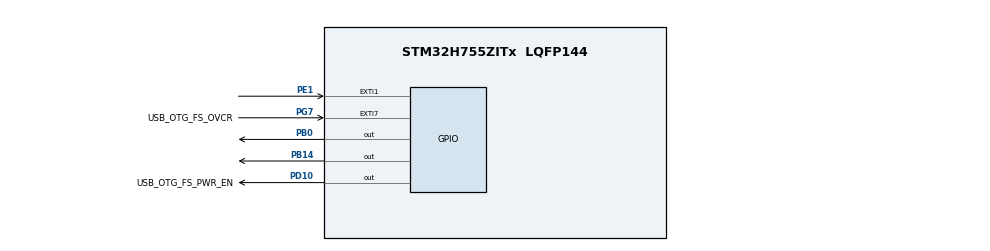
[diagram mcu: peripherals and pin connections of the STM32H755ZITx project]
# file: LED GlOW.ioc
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CortexM4.IPs=FATFS_M4\:I,FREERTOS_M4\:I,IWDG2\:I,RCC,WWDG2\:I,DMA,BDMA,MDMA,NVIC2\:I,ETH,USART3,DEBUG,PDM2PCM_M4\:I,PWR,RESMGR_UTILITY,SYS_M4\:I,USB_DEVICE_M4\:I,USB_HOST_M4\:I,CORTEX_M4\:I,GPIO,OPENAMP_M4\:I,VREFBUF,NUCLEO-H755ZI-Q
CortexM7.IPs=FATFS_M7\:I,FREERTOS_M7\:I,IWDG1\:I,RCC\:I,WWDG1\:I,DMA\:I,BDMA\:I,MDMA\:I,NVIC1\:I,ETH\:I,USART3\:I,USB_OTG_FS\:I,USB_OTG_FS1\:I,SYS\:I,CORTEX_M7\:I,DEBUG\:I,PDM2PCM_M7\:I,PWR\:I,RESMGR_UTILITY\:I,USB_DEVICE_M7\:I,USB_HOST_M7\:I,GPIO\:I,OPENAMP_M7\:I,VREFBUF\:I,NUCLEO-H755ZI-Q\:I
CortexM7.Pins=PB0,PB14,PE1
Mcu.Family=STM32H7
Mcu.Name=STM32H755ZITx
Mcu.Package=LQFP144
NUCLEO-H755ZI-Q.BUTTON=1
NUCLEO-H755ZI-Q.LD1=true
NUCLEO-H755ZI-Q.LD2=true
NUCLEO-H755ZI-Q.LD3=true
NUCLEO-H755ZI-Q.VCP=true
NVIC1.EXTI15_10_IRQn=true\:0\:0\:false\:false\:true\:false\:true\:true
NVIC1.PriorityGroup=NVIC_PRIORITYGROUP_4
NVIC2.PriorityGroup=NVIC_PRIORITYGROUP_4
PA1.PinAttribute=CortexM7
PA1.Signal=ETH_REF_CLK
PA11.PinAttribute=CortexM7
PA11.Signal=USB_OTG_FS_DM
PA12.PinAttribute=CortexM7
PA12.Signal=USB_OTG_FS_DP
PA2.PinAttribute=CortexM7
PA2.Signal=ETH_MDIO
PA7.PinAttribute=CortexM7
PA7.Signal=ETH_CRS_DV
PA8.PinAttribute=CortexM7
PA8.Signal=USB_OTG_FS_SOF
PA9.PinAttribute=CortexM7
PA9.Signal=USB_OTG_FS_VBUS
PB0.PinAttribute=CortexM7
PB0.Signal=GPIO_Output
PB13.PinAttribute=CortexM7
PB13.Signal=ETH_TXD1
PB14.PinAttribute=CortexM7
PB14.Signal=GPIO_Output
PC1.PinAttribute=CortexM7
PC1.Signal=ETH_MDC
PC14-OSC32_IN\ (OSC32_IN).PinAttribute=Free
PC14-OSC32_IN\ (OSC32_IN).Signal=RCC_OSC32_IN
PC15-OSC32_OUT\ (OSC32_OUT).PinAttribute=Free
PC15-OSC32_OUT\ (OSC32_OUT).Signal=RCC_OSC32_OUT
PC4.PinAttribute=CortexM7
PC4.Signal=ETH_RXD0
PC5.PinAttribute=CortexM7
PC5.Signal=ETH_RXD1
PD10.GPIO_Label=USB_OTG_FS_PWR_EN
PD10.PinAttribute=Free
PD10.Signal=GPIO_Output
PD8.Signal=USART3_TX
PD9.Signal=USART3_RX
PE1.PinAttribute=CortexM7
PE1.Signal=GPXTI1
PG11.PinAttribute=CortexM7
PG11.Signal=ETH_TX_EN
PG13.PinAttribute=CortexM7
PG13.Signal=ETH_TXD0
PG7.GPIO_Label=USB_OTG_FS_OVCR
PG7.PinAttribute=Free
PG7.Signal=GPXTI7
PH0-OSC_IN\ (PH0).PinAttribute=Free
PH0-OSC_IN\ (PH0).Signal=RCC_OSC_IN
PH1-OSC_OUT\ (PH1).PinAttribute=Free
PH1-OSC_OUT\ (PH1).Signal=RCC_OSC_OUT
ProjectManager.HeapSize=M4-0x200,M7-0x200
ProjectManager.StackSize=M4-0x400,M7-0x400
ProjectManager.TargetToolchain=STM32CubeIDE
RCC.ADCFreq_Value=129000000
RCC.APB1Freq_Value=112500000
RCC.APB2Freq_Value=112500000
RCC.APB3Freq_Value=112500000
RCC.APB4Freq_Value=112500000
RCC.CortexFreq_Value=225000000
RCC.D1PPRE=RCC_APB3_DIV2
RCC.D2PPRE1=RCC_APB1_DIV2
RCC.D2PPRE2=RCC_APB2_DIV2
RCC.D3PPRE=RCC_APB4_DIV2
RCC.DIVM1=4
RCC.DIVN1=28
RCC.DIVQ1=5
RCC.HCLKFreq_Value=225000000
RCC.PLL2FRACN=0
RCC.PLL3FRACN=0
RCC.PLLFRACN=1024
RCC.SYSCLKFreq_VALUE=225000000
RCC.SYSCLKSource=RCC_SYSCLKSOURCE_PLLCLK
RCC.SupplySource=PWR_DIRECT_SMPS_SUPPLY
RCC.USBFreq_Value=90000000
VP_NUCLEO-H755ZI-Q_VS_BSP_COMMON.Mode=COMMON
VP_SYS_M4_VS_Systick.Mode=SysTick
board=NUCLEO-H755ZI-Q

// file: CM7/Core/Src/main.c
/* USER CODE BEGIN Header */
/**
  ******************************************************************************
  * @file           : main.c
  * @brief          : Main program body
  ******************************************************************************
  */
/* USER CODE END Header */
#include "main.h"

/* USER CODE BEGIN PD */

// Comment this line to disable dual core synchronization
// #define DUAL_CORE_BOOT_SYNC_SEQUENCE

#if defined(DUAL_CORE_BOOT_SYNC_SEQUENCE)
#ifndef HSEM_ID_0
#define HSEM_ID_0 (0U)
#endif
#endif

/* USER CODE END PD */

COM_InitTypeDef BspCOMInit;

void SystemClock_Config(void);
static void MX_GPIO_Init(void);

int main(void)
{

  /* MCU Configuration--------------------------------------------------------*/

  /* Reset of all peripherals, Initializes the Flash interface and the Systick. */
  HAL_Init();

  /* Configure the system clock */
  SystemClock_Config();

  /* Initialize all configured peripherals */
  MX_GPIO_Init();

  /* Infinite loop */
  while (1)
  {

    /* USER CODE BEGIN 3 */

    HAL_GPIO_TogglePin(GPIOB, GPIO_PIN_0);   // Green LED (LD1)
    HAL_GPIO_TogglePin(GPIOE, GPIO_PIN_1);   // Yellow LED (LD2)
    HAL_GPIO_TogglePin(GPIOB, GPIO_PIN_14);  // Red LED (LD3)

    HAL_Delay(400);

    /* USER CODE END 3 */
  }
}

void SystemClock_Config(void)
{
  RCC_OscInitTypeDef RCC_OscInitStruct = {0};
  RCC_ClkInitTypeDef RCC_ClkInitStruct = {0};

  /** Supply configuration update enable
  */
  HAL_PWREx_ConfigSupply(PWR_DIRECT_SMPS_SUPPLY);

  /** Configure the main internal regulator output voltage
  */
  while(!__HAL_PWR_GET_FLAG(PWR_FLAG_VOSRDY)) {}

  /** Initializes the RCC Oscillators
  */
  RCC_OscInitStruct.OscillatorType = RCC_OSCILLATORTYPE_HSI;
  RCC_OscInitStruct.HSIState = RCC_HSI_DIV1;
  RCC_OscInitStruct.HSICalibrationValue = RCC_HSICALIBRATION_DEFAULT;
  RCC_OscInitStruct.PLL.PLLState = RCC_PLL_ON;
  RCC_OscInitStruct.PLL.PLLSource = RCC_PLLSOURCE_HSI;
  RCC_OscInitStruct.PLL.PLLM = 4;
  RCC_OscInitStruct.PLL.PLLN = 28;
  RCC_OscInitStruct.PLL.PLLP = 2;
  RCC_OscInitStruct.PLL.PLLQ = 5;
  RCC_OscInitStruct.PLL.PLLR = 2;
  RCC_OscInitStruct.PLL.PLLRGE = RCC_PLL1VCIRANGE_3;
  RCC_OscInitStruct.PLL.PLLVCOSEL = RCC_PLL1VCOWIDE;
  RCC_OscInitStruct.PLL.PLLFRACN = 0;
  if (HAL_RCC_OscConfig(&RCC_OscInitStruct) != HAL_OK)
  {
    Error_Handler();
  }

  /** Initializes the CPU, AHB and APB buses clocks
  */
  RCC_ClkInitStruct.ClockType = RCC_CLOCKTYPE_HCLK|RCC_CLOCKTYPE_SYSCLK
                              |RCC_CLOCKTYPE_PCLK1|RCC_CLOCKTYPE_PCLK2
                              |RCC_CLOCKTYPE_D3PCLK1|RCC_CLOCKTYPE_D1PCLK1;
  RCC_ClkInitStruct.SYSCLKSource = RCC_SYSCLKSOURCE_PLLCLK;
  RCC_ClkInitStruct.SYSCLKDivider = RCC_SYSCLK_DIV1;
  RCC_ClkInitStruct.AHBCLKDivider = RCC_HCLK_DIV2;
  RCC_ClkInitStruct.APB3CLKDivider = RCC_APB3_DIV2;
  RCC_ClkInitStruct.APB1CLKDivider = RCC_APB1_DIV2;
  RCC_ClkInitStruct.APB2CLKDivider = RCC_APB2_DIV2;
  RCC_ClkInitStruct.APB4CLKDivider = RCC_APB4_DIV2;

  if (HAL_RCC_ClockConfig(&RCC_ClkInitStruct, FLASH_LATENCY_2) != HAL_OK)
  {
    Error_Handler();
  }
}

static void MX_GPIO_Init(void)
{
  GPIO_InitTypeDef GPIO_InitStruct = {0};

  /* GPIO Ports Clock Enable */
  __HAL_RCC_GPIOB_CLK_ENABLE();
  __HAL_RCC_GPIOE_CLK_ENABLE();

  /*Configure GPIO pin Output Level */
  HAL_GPIO_WritePin(GPIOB, GPIO_PIN_0|GPIO_PIN_14, GPIO_PIN_RESET);
  HAL_GPIO_WritePin(GPIOE, GPIO_PIN_1, GPIO_PIN_RESET);

  /*Configure GPIO pins : PB0 PB14 (Green + Red LED) */
  GPIO_InitStruct.Pin = GPIO_PIN_0|GPIO_PIN_14;
  GPIO_InitStruct.Mode = GPIO_MODE_OUTPUT_PP;
  GPIO_InitStruct.Pull = GPIO_NOPULL;
  GPIO_InitStruct.Speed = GPIO_SPEED_FREQ_LOW;
  HAL_GPIO_Init(GPIOB, &GPIO_InitStruct);

  /*Configure GPIO pin : PE1 (Yellow LED) */
  GPIO_InitStruct.Pin = GPIO_PIN_1;
  GPIO_InitStruct.Mode = GPIO_MODE_OUTPUT_PP;     // ← Corrected
  GPIO_InitStruct.Pull = GPIO_NOPULL;
  GPIO_InitStruct.Speed = GPIO_SPEED_FREQ_LOW;
  HAL_GPIO_Init(GPIOE, &GPIO_InitStruct);
}

void Error_Handler(void)
{
  __disable_irq();
  while (1)
  {
  }
}
